##
## LEF for PtnCells ;
## created by Innovus v15.23-s045_1 on Sat Mar  7 15:14:19 2026
##

VERSION 5.8 ;

BUSBITCHARS "[]" ;
DIVIDERCHAR "/" ;

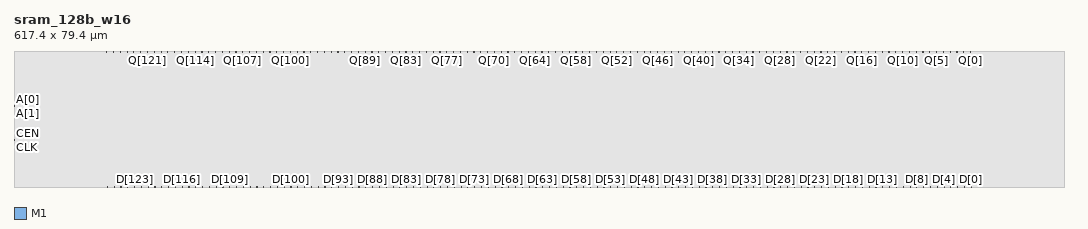
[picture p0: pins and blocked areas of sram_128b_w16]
MACRO sram_128b_w16
  CLASS BLOCK ;
  SIZE 617.4000 BY 79.4000 ;
  FOREIGN sram_128b_w16 0.0000 0.0000 ;
  ORIGIN 0 0 ;
  SYMMETRY X Y R90 ;
  PIN CLK
    DIRECTION INPUT ;
    USE SIGNAL ;
    PORT
      LAYER M1 ;
        RECT 0.0000 27.5550 0.4700 27.6450 ;
    END
  END CLK
  PIN D[127]
    DIRECTION INPUT ;
    USE SIGNAL ;
    PORT
      LAYER M1 ;
        RECT 54.8550 0.0000 54.9450 0.4700 ;
    END
  END D[127]
  PIN D[126]
    DIRECTION INPUT ;
    USE SIGNAL ;
    PORT
      LAYER M1 ;
        RECT 58.8550 0.0000 58.9450 0.4700 ;
    END
  END D[126]
  PIN D[125]
    DIRECTION INPUT ;
    USE SIGNAL ;
    PORT
      LAYER M1 ;
        RECT 62.8550 0.0000 62.9450 0.4700 ;
    END
  END D[125]
  PIN D[124]
    DIRECTION INPUT ;
    USE SIGNAL ;
    PORT
      LAYER M1 ;
        RECT 66.8550 0.0000 66.9450 0.4700 ;
    END
  END D[124]
  PIN D[123]
    DIRECTION INPUT ;
    USE SIGNAL ;
    PORT
      LAYER M1 ;
        RECT 70.8550 0.0000 70.9450 0.4700 ;
    END
  END D[123]
  PIN D[122]
    DIRECTION INPUT ;
    USE SIGNAL ;
    PORT
      LAYER M1 ;
        RECT 74.8550 0.0000 74.9450 0.4700 ;
    END
  END D[122]
  PIN D[121]
    DIRECTION INPUT ;
    USE SIGNAL ;
    PORT
      LAYER M1 ;
        RECT 78.8550 0.0000 78.9450 0.4700 ;
    END
  END D[121]
  PIN D[120]
    DIRECTION INPUT ;
    USE SIGNAL ;
    PORT
      LAYER M1 ;
        RECT 82.8550 0.0000 82.9450 0.4700 ;
    END
  END D[120]
  PIN D[119]
    DIRECTION INPUT ;
    USE SIGNAL ;
    PORT
      LAYER M1 ;
        RECT 86.8550 0.0000 86.9450 0.4700 ;
    END
  END D[119]
  PIN D[118]
    DIRECTION INPUT ;
    USE SIGNAL ;
    PORT
      LAYER M1 ;
        RECT 90.8550 0.0000 90.9450 0.4700 ;
    END
  END D[118]
  PIN D[117]
    DIRECTION INPUT ;
    USE SIGNAL ;
    PORT
      LAYER M1 ;
        RECT 94.8550 0.0000 94.9450 0.4700 ;
    END
  END D[117]
  PIN D[116]
    DIRECTION INPUT ;
    USE SIGNAL ;
    PORT
      LAYER M1 ;
        RECT 98.8550 0.0000 98.9450 0.4700 ;
    END
  END D[116]
  PIN D[115]
    DIRECTION INPUT ;
    USE SIGNAL ;
    PORT
      LAYER M1 ;
        RECT 102.8550 0.0000 102.9450 0.4700 ;
    END
  END D[115]
  PIN D[114]
    DIRECTION INPUT ;
    USE SIGNAL ;
    PORT
      LAYER M1 ;
        RECT 106.8550 0.0000 106.9450 0.4700 ;
    END
  END D[114]
  PIN D[113]
    DIRECTION INPUT ;
    USE SIGNAL ;
    PORT
      LAYER M1 ;
        RECT 110.8550 0.0000 110.9450 0.4700 ;
    END
  END D[113]
  PIN D[112]
    DIRECTION INPUT ;
    USE SIGNAL ;
    PORT
      LAYER M1 ;
        RECT 114.8550 0.0000 114.9450 0.4700 ;
    END
  END D[112]
  PIN D[111]
    DIRECTION INPUT ;
    USE SIGNAL ;
    PORT
      LAYER M1 ;
        RECT 118.8550 0.0000 118.9450 0.4700 ;
    END
  END D[111]
  PIN D[110]
    DIRECTION INPUT ;
    USE SIGNAL ;
    PORT
      LAYER M1 ;
        RECT 122.8550 0.0000 122.9450 0.4700 ;
    END
  END D[110]
  PIN D[109]
    DIRECTION INPUT ;
    USE SIGNAL ;
    PORT
      LAYER M1 ;
        RECT 126.8550 0.0000 126.9450 0.4700 ;
    END
  END D[109]
  PIN D[108]
    DIRECTION INPUT ;
    USE SIGNAL ;
    PORT
      LAYER M1 ;
        RECT 130.8550 0.0000 130.9450 0.4700 ;
    END
  END D[108]
  PIN D[107]
    DIRECTION INPUT ;
    USE SIGNAL ;
    PORT
      LAYER M1 ;
        RECT 134.8550 0.0000 134.9450 0.4700 ;
    END
  END D[107]
  PIN D[106]
    DIRECTION INPUT ;
    USE SIGNAL ;
    PORT
      LAYER M1 ;
        RECT 138.8550 0.0000 138.9450 0.4700 ;
    END
  END D[106]
  PIN D[105]
    DIRECTION INPUT ;
    USE SIGNAL ;
    PORT
      LAYER M1 ;
        RECT 142.8550 0.0000 142.9450 0.4700 ;
    END
  END D[105]
  PIN D[104]
    DIRECTION INPUT ;
    USE SIGNAL ;
    PORT
      LAYER M1 ;
        RECT 146.8550 0.0000 146.9450 0.4700 ;
    END
  END D[104]
  PIN D[103]
    DIRECTION INPUT ;
    USE SIGNAL ;
    PORT
      LAYER M1 ;
        RECT 150.8550 0.0000 150.9450 0.4700 ;
    END
  END D[103]
  PIN D[102]
    DIRECTION INPUT ;
    USE SIGNAL ;
    PORT
      LAYER M1 ;
        RECT 154.8550 0.0000 154.9450 0.4700 ;
    END
  END D[102]
  PIN D[101]
    DIRECTION INPUT ;
    USE SIGNAL ;
    PORT
      LAYER M1 ;
        RECT 158.8550 0.0000 158.9450 0.4700 ;
    END
  END D[101]
  PIN D[100]
    DIRECTION INPUT ;
    USE SIGNAL ;
    PORT
      LAYER M1 ;
        RECT 162.8550 0.0000 162.9450 0.4700 ;
    END
  END D[100]
  PIN D[99]
    DIRECTION INPUT ;
    USE SIGNAL ;
    PORT
      LAYER M1 ;
        RECT 166.8550 0.0000 166.9450 0.4700 ;
    END
  END D[99]
  PIN D[98]
    DIRECTION INPUT ;
    USE SIGNAL ;
    PORT
      LAYER M1 ;
        RECT 170.8550 0.0000 170.9450 0.4700 ;
    END
  END D[98]
  PIN D[97]
    DIRECTION INPUT ;
    USE SIGNAL ;
    PORT
      LAYER M1 ;
        RECT 174.8550 0.0000 174.9450 0.4700 ;
    END
  END D[97]
  PIN D[96]
    DIRECTION INPUT ;
    USE SIGNAL ;
    PORT
      LAYER M1 ;
        RECT 178.8550 0.0000 178.9450 0.4700 ;
    END
  END D[96]
  PIN D[95]
    DIRECTION INPUT ;
    USE SIGNAL ;
    PORT
      LAYER M1 ;
        RECT 182.8550 0.0000 182.9450 0.4700 ;
    END
  END D[95]
  PIN D[94]
    DIRECTION INPUT ;
    USE SIGNAL ;
    PORT
      LAYER M1 ;
        RECT 186.8550 0.0000 186.9450 0.4700 ;
    END
  END D[94]
  PIN D[93]
    DIRECTION INPUT ;
    USE SIGNAL ;
    PORT
      LAYER M1 ;
        RECT 190.8550 0.0000 190.9450 0.4700 ;
    END
  END D[93]
  PIN D[92]
    DIRECTION INPUT ;
    USE SIGNAL ;
    PORT
      LAYER M1 ;
        RECT 194.8550 0.0000 194.9450 0.4700 ;
    END
  END D[92]
  PIN D[91]
    DIRECTION INPUT ;
    USE SIGNAL ;
    PORT
      LAYER M1 ;
        RECT 198.8550 0.0000 198.9450 0.4700 ;
    END
  END D[91]
  PIN D[90]
    DIRECTION INPUT ;
    USE SIGNAL ;
    PORT
      LAYER M1 ;
        RECT 202.8550 0.0000 202.9450 0.4700 ;
    END
  END D[90]
  PIN D[89]
    DIRECTION INPUT ;
    USE SIGNAL ;
    PORT
      LAYER M1 ;
        RECT 206.8550 0.0000 206.9450 0.4700 ;
    END
  END D[89]
  PIN D[88]
    DIRECTION INPUT ;
    USE SIGNAL ;
    PORT
      LAYER M1 ;
        RECT 210.8550 0.0000 210.9450 0.4700 ;
    END
  END D[88]
  PIN D[87]
    DIRECTION INPUT ;
    USE SIGNAL ;
    PORT
      LAYER M1 ;
        RECT 214.8550 0.0000 214.9450 0.4700 ;
    END
  END D[87]
  PIN D[86]
    DIRECTION INPUT ;
    USE SIGNAL ;
    PORT
      LAYER M1 ;
        RECT 218.8550 0.0000 218.9450 0.4700 ;
    END
  END D[86]
  PIN D[85]
    DIRECTION INPUT ;
    USE SIGNAL ;
    PORT
      LAYER M1 ;
        RECT 222.8550 0.0000 222.9450 0.4700 ;
    END
  END D[85]
  PIN D[84]
    DIRECTION INPUT ;
    USE SIGNAL ;
    PORT
      LAYER M1 ;
        RECT 226.8550 0.0000 226.9450 0.4700 ;
    END
  END D[84]
  PIN D[83]
    DIRECTION INPUT ;
    USE SIGNAL ;
    PORT
      LAYER M1 ;
        RECT 230.8550 0.0000 230.9450 0.4700 ;
    END
  END D[83]
  PIN D[82]
    DIRECTION INPUT ;
    USE SIGNAL ;
    PORT
      LAYER M1 ;
        RECT 234.8550 0.0000 234.9450 0.4700 ;
    END
  END D[82]
  PIN D[81]
    DIRECTION INPUT ;
    USE SIGNAL ;
    PORT
      LAYER M1 ;
        RECT 238.8550 0.0000 238.9450 0.4700 ;
    END
  END D[81]
  PIN D[80]
    DIRECTION INPUT ;
    USE SIGNAL ;
    PORT
      LAYER M1 ;
        RECT 242.8550 0.0000 242.9450 0.4700 ;
    END
  END D[80]
  PIN D[79]
    DIRECTION INPUT ;
    USE SIGNAL ;
    PORT
      LAYER M1 ;
        RECT 246.8550 0.0000 246.9450 0.4700 ;
    END
  END D[79]
  PIN D[78]
    DIRECTION INPUT ;
    USE SIGNAL ;
    PORT
      LAYER M1 ;
        RECT 250.8550 0.0000 250.9450 0.4700 ;
    END
  END D[78]
  PIN D[77]
    DIRECTION INPUT ;
    USE SIGNAL ;
    PORT
      LAYER M1 ;
        RECT 254.8550 0.0000 254.9450 0.4700 ;
    END
  END D[77]
  PIN D[76]
    DIRECTION INPUT ;
    USE SIGNAL ;
    PORT
      LAYER M1 ;
        RECT 258.8550 0.0000 258.9450 0.4700 ;
    END
  END D[76]
  PIN D[75]
    DIRECTION INPUT ;
    USE SIGNAL ;
    PORT
      LAYER M1 ;
        RECT 262.8550 0.0000 262.9450 0.4700 ;
    END
  END D[75]
  PIN D[74]
    DIRECTION INPUT ;
    USE SIGNAL ;
    PORT
      LAYER M1 ;
        RECT 266.8550 0.0000 266.9450 0.4700 ;
    END
  END D[74]
  PIN D[73]
    DIRECTION INPUT ;
    USE SIGNAL ;
    PORT
      LAYER M1 ;
        RECT 270.8550 0.0000 270.9450 0.4700 ;
    END
  END D[73]
  PIN D[72]
    DIRECTION INPUT ;
    USE SIGNAL ;
    PORT
      LAYER M1 ;
        RECT 274.8550 0.0000 274.9450 0.4700 ;
    END
  END D[72]
  PIN D[71]
    DIRECTION INPUT ;
    USE SIGNAL ;
    PORT
      LAYER M1 ;
        RECT 278.8550 0.0000 278.9450 0.4700 ;
    END
  END D[71]
  PIN D[70]
    DIRECTION INPUT ;
    USE SIGNAL ;
    PORT
      LAYER M1 ;
        RECT 282.8550 0.0000 282.9450 0.4700 ;
    END
  END D[70]
  PIN D[69]
    DIRECTION INPUT ;
    USE SIGNAL ;
    PORT
      LAYER M1 ;
        RECT 286.8550 0.0000 286.9450 0.4700 ;
    END
  END D[69]
  PIN D[68]
    DIRECTION INPUT ;
    USE SIGNAL ;
    PORT
      LAYER M1 ;
        RECT 290.8550 0.0000 290.9450 0.4700 ;
    END
  END D[68]
  PIN D[67]
    DIRECTION INPUT ;
    USE SIGNAL ;
    PORT
      LAYER M1 ;
        RECT 294.8550 0.0000 294.9450 0.4700 ;
    END
  END D[67]
  PIN D[66]
    DIRECTION INPUT ;
    USE SIGNAL ;
    PORT
      LAYER M1 ;
        RECT 298.8550 0.0000 298.9450 0.4700 ;
    END
  END D[66]
  PIN D[65]
    DIRECTION INPUT ;
    USE SIGNAL ;
    PORT
      LAYER M1 ;
        RECT 302.8550 0.0000 302.9450 0.4700 ;
    END
  END D[65]
  PIN D[64]
    DIRECTION INPUT ;
    USE SIGNAL ;
    PORT
      LAYER M1 ;
        RECT 306.8550 0.0000 306.9450 0.4700 ;
    END
  END D[64]
  PIN D[63]
    DIRECTION INPUT ;
    USE SIGNAL ;
    PORT
      LAYER M1 ;
        RECT 310.8550 0.0000 310.9450 0.4700 ;
    END
  END D[63]
  PIN D[62]
    DIRECTION INPUT ;
    USE SIGNAL ;
    PORT
      LAYER M1 ;
        RECT 314.8550 0.0000 314.9450 0.4700 ;
    END
  END D[62]
  PIN D[61]
    DIRECTION INPUT ;
    USE SIGNAL ;
    PORT
      LAYER M1 ;
        RECT 318.8550 0.0000 318.9450 0.4700 ;
    END
  END D[61]
  PIN D[60]
    DIRECTION INPUT ;
    USE SIGNAL ;
    PORT
      LAYER M1 ;
        RECT 322.8550 0.0000 322.9450 0.4700 ;
    END
  END D[60]
  PIN D[59]
    DIRECTION INPUT ;
    USE SIGNAL ;
    PORT
      LAYER M1 ;
        RECT 326.8550 0.0000 326.9450 0.4700 ;
    END
  END D[59]
  PIN D[58]
    DIRECTION INPUT ;
    USE SIGNAL ;
    PORT
      LAYER M1 ;
        RECT 330.8550 0.0000 330.9450 0.4700 ;
    END
  END D[58]
  PIN D[57]
    DIRECTION INPUT ;
    USE SIGNAL ;
    PORT
      LAYER M1 ;
        RECT 334.8550 0.0000 334.9450 0.4700 ;
    END
  END D[57]
  PIN D[56]
    DIRECTION INPUT ;
    USE SIGNAL ;
    PORT
      LAYER M1 ;
        RECT 338.8550 0.0000 338.9450 0.4700 ;
    END
  END D[56]
  PIN D[55]
    DIRECTION INPUT ;
    USE SIGNAL ;
    PORT
      LAYER M1 ;
        RECT 342.8550 0.0000 342.9450 0.4700 ;
    END
  END D[55]
  PIN D[54]
    DIRECTION INPUT ;
    USE SIGNAL ;
    PORT
      LAYER M1 ;
        RECT 346.8550 0.0000 346.9450 0.4700 ;
    END
  END D[54]
  PIN D[53]
    DIRECTION INPUT ;
    USE SIGNAL ;
    PORT
      LAYER M1 ;
        RECT 350.8550 0.0000 350.9450 0.4700 ;
    END
  END D[53]
  PIN D[52]
    DIRECTION INPUT ;
    USE SIGNAL ;
    PORT
      LAYER M1 ;
        RECT 354.8550 0.0000 354.9450 0.4700 ;
    END
  END D[52]
  PIN D[51]
    DIRECTION INPUT ;
    USE SIGNAL ;
    PORT
      LAYER M1 ;
        RECT 358.8550 0.0000 358.9450 0.4700 ;
    END
  END D[51]
  PIN D[50]
    DIRECTION INPUT ;
    USE SIGNAL ;
    PORT
      LAYER M1 ;
        RECT 362.8550 0.0000 362.9450 0.4700 ;
    END
  END D[50]
  PIN D[49]
    DIRECTION INPUT ;
    USE SIGNAL ;
    PORT
      LAYER M1 ;
        RECT 366.8550 0.0000 366.9450 0.4700 ;
    END
  END D[49]
  PIN D[48]
    DIRECTION INPUT ;
    USE SIGNAL ;
    PORT
      LAYER M1 ;
        RECT 370.8550 0.0000 370.9450 0.4700 ;
    END
  END D[48]
  PIN D[47]
    DIRECTION INPUT ;
    USE SIGNAL ;
    PORT
      LAYER M1 ;
        RECT 374.8550 0.0000 374.9450 0.4700 ;
    END
  END D[47]
  PIN D[46]
    DIRECTION INPUT ;
    USE SIGNAL ;
    PORT
      LAYER M1 ;
        RECT 378.8550 0.0000 378.9450 0.4700 ;
    END
  END D[46]
  PIN D[45]
    DIRECTION INPUT ;
    USE SIGNAL ;
    PORT
      LAYER M1 ;
        RECT 382.8550 0.0000 382.9450 0.4700 ;
    END
  END D[45]
  PIN D[44]
    DIRECTION INPUT ;
    USE SIGNAL ;
    PORT
      LAYER M1 ;
        RECT 386.8550 0.0000 386.9450 0.4700 ;
    END
  END D[44]
  PIN D[43]
    DIRECTION INPUT ;
    USE SIGNAL ;
    PORT
      LAYER M1 ;
        RECT 390.8550 0.0000 390.9450 0.4700 ;
    END
  END D[43]
  PIN D[42]
    DIRECTION INPUT ;
    USE SIGNAL ;
    PORT
      LAYER M1 ;
        RECT 394.8550 0.0000 394.9450 0.4700 ;
    END
  END D[42]
  PIN D[41]
    DIRECTION INPUT ;
    USE SIGNAL ;
    PORT
      LAYER M1 ;
        RECT 398.8550 0.0000 398.9450 0.4700 ;
    END
  END D[41]
  PIN D[40]
    DIRECTION INPUT ;
    USE SIGNAL ;
    PORT
      LAYER M1 ;
        RECT 402.8550 0.0000 402.9450 0.4700 ;
    END
  END D[40]
  PIN D[39]
    DIRECTION INPUT ;
    USE SIGNAL ;
    PORT
      LAYER M1 ;
        RECT 406.8550 0.0000 406.9450 0.4700 ;
    END
  END D[39]
  PIN D[38]
    DIRECTION INPUT ;
    USE SIGNAL ;
    PORT
      LAYER M1 ;
        RECT 410.8550 0.0000 410.9450 0.4700 ;
    END
  END D[38]
  PIN D[37]
    DIRECTION INPUT ;
    USE SIGNAL ;
    PORT
      LAYER M1 ;
        RECT 414.8550 0.0000 414.9450 0.4700 ;
    END
  END D[37]
  PIN D[36]
    DIRECTION INPUT ;
    USE SIGNAL ;
    PORT
      LAYER M1 ;
        RECT 418.8550 0.0000 418.9450 0.4700 ;
    END
  END D[36]
  PIN D[35]
    DIRECTION INPUT ;
    USE SIGNAL ;
    PORT
      LAYER M1 ;
        RECT 422.8550 0.0000 422.9450 0.4700 ;
    END
  END D[35]
  PIN D[34]
    DIRECTION INPUT ;
    USE SIGNAL ;
    PORT
      LAYER M1 ;
        RECT 426.8550 0.0000 426.9450 0.4700 ;
    END
  END D[34]
  PIN D[33]
    DIRECTION INPUT ;
    USE SIGNAL ;
    PORT
      LAYER M1 ;
        RECT 430.8550 0.0000 430.9450 0.4700 ;
    END
  END D[33]
  PIN D[32]
    DIRECTION INPUT ;
    USE SIGNAL ;
    PORT
      LAYER M1 ;
        RECT 434.8550 0.0000 434.9450 0.4700 ;
    END
  END D[32]
  PIN D[31]
    DIRECTION INPUT ;
    USE SIGNAL ;
    PORT
      LAYER M1 ;
        RECT 438.8550 0.0000 438.9450 0.4700 ;
    END
  END D[31]
  PIN D[30]
    DIRECTION INPUT ;
    USE SIGNAL ;
    PORT
      LAYER M1 ;
        RECT 442.8550 0.0000 442.9450 0.4700 ;
    END
  END D[30]
  PIN D[29]
    DIRECTION INPUT ;
    USE SIGNAL ;
    PORT
      LAYER M1 ;
        RECT 446.8550 0.0000 446.9450 0.4700 ;
    END
  END D[29]
  PIN D[28]
    DIRECTION INPUT ;
    USE SIGNAL ;
    PORT
      LAYER M1 ;
        RECT 450.8550 0.0000 450.9450 0.4700 ;
    END
  END D[28]
  PIN D[27]
    DIRECTION INPUT ;
    USE SIGNAL ;
    PORT
      LAYER M1 ;
        RECT 454.8550 0.0000 454.9450 0.4700 ;
    END
  END D[27]
  PIN D[26]
    DIRECTION INPUT ;
    USE SIGNAL ;
    PORT
      LAYER M1 ;
        RECT 458.8550 0.0000 458.9450 0.4700 ;
    END
  END D[26]
  PIN D[25]
    DIRECTION INPUT ;
    USE SIGNAL ;
    PORT
      LAYER M1 ;
        RECT 462.8550 0.0000 462.9450 0.4700 ;
    END
  END D[25]
  PIN D[24]
    DIRECTION INPUT ;
    USE SIGNAL ;
    PORT
      LAYER M1 ;
        RECT 466.8550 0.0000 466.9450 0.4700 ;
    END
  END D[24]
  PIN D[23]
    DIRECTION INPUT ;
    USE SIGNAL ;
    PORT
      LAYER M1 ;
        RECT 470.8550 0.0000 470.9450 0.4700 ;
    END
  END D[23]
  PIN D[22]
    DIRECTION INPUT ;
    USE SIGNAL ;
    PORT
      LAYER M1 ;
        RECT 474.8550 0.0000 474.9450 0.4700 ;
    END
  END D[22]
  PIN D[21]
    DIRECTION INPUT ;
    USE SIGNAL ;
    PORT
      LAYER M1 ;
        RECT 478.8550 0.0000 478.9450 0.4700 ;
    END
  END D[21]
  PIN D[20]
    DIRECTION INPUT ;
    USE SIGNAL ;
    PORT
      LAYER M1 ;
        RECT 482.8550 0.0000 482.9450 0.4700 ;
    END
  END D[20]
  PIN D[19]
    DIRECTION INPUT ;
    USE SIGNAL ;
    PORT
      LAYER M1 ;
        RECT 486.8550 0.0000 486.9450 0.4700 ;
    END
  END D[19]
  PIN D[18]
    DIRECTION INPUT ;
    USE SIGNAL ;
    PORT
      LAYER M1 ;
        RECT 490.8550 0.0000 490.9450 0.4700 ;
    END
  END D[18]
  PIN D[17]
    DIRECTION INPUT ;
    USE SIGNAL ;
    PORT
      LAYER M1 ;
        RECT 494.8550 0.0000 494.9450 0.4700 ;
    END
  END D[17]
  PIN D[16]
    DIRECTION INPUT ;
    USE SIGNAL ;
    PORT
      LAYER M1 ;
        RECT 498.8550 0.0000 498.9450 0.4700 ;
    END
  END D[16]
  PIN D[15]
    DIRECTION INPUT ;
    USE SIGNAL ;
    PORT
      LAYER M1 ;
        RECT 502.8550 0.0000 502.9450 0.4700 ;
    END
  END D[15]
  PIN D[14]
    DIRECTION INPUT ;
    USE SIGNAL ;
    PORT
      LAYER M1 ;
        RECT 506.8550 0.0000 506.9450 0.4700 ;
    END
  END D[14]
  PIN D[13]
    DIRECTION INPUT ;
    USE SIGNAL ;
    PORT
      LAYER M1 ;
        RECT 510.8550 0.0000 510.9450 0.4700 ;
    END
  END D[13]
  PIN D[12]
    DIRECTION INPUT ;
    USE SIGNAL ;
    PORT
      LAYER M1 ;
        RECT 514.8550 0.0000 514.9450 0.4700 ;
    END
  END D[12]
  PIN D[11]
    DIRECTION INPUT ;
    USE SIGNAL ;
    PORT
      LAYER M1 ;
        RECT 518.8550 0.0000 518.9450 0.4700 ;
    END
  END D[11]
  PIN D[10]
    DIRECTION INPUT ;
    USE SIGNAL ;
    PORT
      LAYER M1 ;
        RECT 522.8550 0.0000 522.9450 0.4700 ;
    END
  END D[10]
  PIN D[9]
    DIRECTION INPUT ;
    USE SIGNAL ;
    PORT
      LAYER M1 ;
        RECT 526.8550 0.0000 526.9450 0.4700 ;
    END
  END D[9]
  PIN D[8]
    DIRECTION INPUT ;
    USE SIGNAL ;
    PORT
      LAYER M1 ;
        RECT 530.8550 0.0000 530.9450 0.4700 ;
    END
  END D[8]
  PIN D[7]
    DIRECTION INPUT ;
    USE SIGNAL ;
    PORT
      LAYER M1 ;
        RECT 534.8550 0.0000 534.9450 0.4700 ;
    END
  END D[7]
  PIN D[6]
    DIRECTION INPUT ;
    USE SIGNAL ;
    PORT
      LAYER M1 ;
        RECT 538.8550 0.0000 538.9450 0.4700 ;
    END
  END D[6]
  PIN D[5]
    DIRECTION INPUT ;
    USE SIGNAL ;
    PORT
      LAYER M1 ;
        RECT 542.8550 0.0000 542.9450 0.4700 ;
    END
  END D[5]
  PIN D[4]
    DIRECTION INPUT ;
    USE SIGNAL ;
    PORT
      LAYER M1 ;
        RECT 546.8550 0.0000 546.9450 0.4700 ;
    END
  END D[4]
  PIN D[3]
    DIRECTION INPUT ;
    USE SIGNAL ;
    PORT
      LAYER M1 ;
        RECT 550.8550 0.0000 550.9450 0.4700 ;
    END
  END D[3]
  PIN D[2]
    DIRECTION INPUT ;
    USE SIGNAL ;
    PORT
      LAYER M1 ;
        RECT 554.8550 0.0000 554.9450 0.4700 ;
    END
  END D[2]
  PIN D[1]
    DIRECTION INPUT ;
    USE SIGNAL ;
    PORT
      LAYER M1 ;
        RECT 558.8550 0.0000 558.9450 0.4700 ;
    END
  END D[1]
  PIN D[0]
    DIRECTION INPUT ;
    USE SIGNAL ;
    PORT
      LAYER M1 ;
        RECT 562.8550 0.0000 562.9450 0.4700 ;
    END
  END D[0]
  PIN Q[127]
    DIRECTION OUTPUT ;
    USE SIGNAL ;
    PORT
      LAYER M1 ;
        RECT 54.4550 78.9300 54.5450 79.4000 ;
    END
  END Q[127]
  PIN Q[126]
    DIRECTION OUTPUT ;
    USE SIGNAL ;
    PORT
      LAYER M1 ;
        RECT 58.4550 78.9300 58.5450 79.4000 ;
    END
  END Q[126]
  PIN Q[125]
    DIRECTION OUTPUT ;
    USE SIGNAL ;
    PORT
      LAYER M1 ;
        RECT 62.4550 78.9300 62.5450 79.4000 ;
    END
  END Q[125]
  PIN Q[124]
    DIRECTION OUTPUT ;
    USE SIGNAL ;
    PORT
      LAYER M1 ;
        RECT 66.4550 78.9300 66.5450 79.4000 ;
    END
  END Q[124]
  PIN Q[123]
    DIRECTION OUTPUT ;
    USE SIGNAL ;
    PORT
      LAYER M1 ;
        RECT 70.4550 78.9300 70.5450 79.4000 ;
    END
  END Q[123]
  PIN Q[122]
    DIRECTION OUTPUT ;
    USE SIGNAL ;
    PORT
      LAYER M1 ;
        RECT 74.4550 78.9300 74.5450 79.4000 ;
    END
  END Q[122]
  PIN Q[121]
    DIRECTION OUTPUT ;
    USE SIGNAL ;
    PORT
      LAYER M1 ;
        RECT 78.4550 78.9300 78.5450 79.4000 ;
    END
  END Q[121]
  PIN Q[120]
    DIRECTION OUTPUT ;
    USE SIGNAL ;
    PORT
      LAYER M1 ;
        RECT 82.4550 78.9300 82.5450 79.4000 ;
    END
  END Q[120]
  PIN Q[119]
    DIRECTION OUTPUT ;
    USE SIGNAL ;
    PORT
      LAYER M1 ;
        RECT 86.4550 78.9300 86.5450 79.4000 ;
    END
  END Q[119]
  PIN Q[118]
    DIRECTION OUTPUT ;
    USE SIGNAL ;
    PORT
      LAYER M1 ;
        RECT 90.4550 78.9300 90.5450 79.4000 ;
    END
  END Q[118]
  PIN Q[117]
    DIRECTION OUTPUT ;
    USE SIGNAL ;
    PORT
      LAYER M1 ;
        RECT 94.4550 78.9300 94.5450 79.4000 ;
    END
  END Q[117]
  PIN Q[116]
    DIRECTION OUTPUT ;
    USE SIGNAL ;
    PORT
      LAYER M1 ;
        RECT 98.4550 78.9300 98.5450 79.4000 ;
    END
  END Q[116]
  PIN Q[115]
    DIRECTION OUTPUT ;
    USE SIGNAL ;
    PORT
      LAYER M1 ;
        RECT 102.4550 78.9300 102.5450 79.4000 ;
    END
  END Q[115]
  PIN Q[114]
    DIRECTION OUTPUT ;
    USE SIGNAL ;
    PORT
      LAYER M1 ;
        RECT 106.4550 78.9300 106.5450 79.4000 ;
    END
  END Q[114]
  PIN Q[113]
    DIRECTION OUTPUT ;
    USE SIGNAL ;
    PORT
      LAYER M1 ;
        RECT 110.4550 78.9300 110.5450 79.4000 ;
    END
  END Q[113]
  PIN Q[112]
    DIRECTION OUTPUT ;
    USE SIGNAL ;
    PORT
      LAYER M1 ;
        RECT 114.4550 78.9300 114.5450 79.4000 ;
    END
  END Q[112]
  PIN Q[111]
    DIRECTION OUTPUT ;
    USE SIGNAL ;
    PORT
      LAYER M1 ;
        RECT 118.4550 78.9300 118.5450 79.4000 ;
    END
  END Q[111]
  PIN Q[110]
    DIRECTION OUTPUT ;
    USE SIGNAL ;
    PORT
      LAYER M1 ;
        RECT 122.4550 78.9300 122.5450 79.4000 ;
    END
  END Q[110]
  PIN Q[109]
    DIRECTION OUTPUT ;
    USE SIGNAL ;
    PORT
      LAYER M1 ;
        RECT 126.4550 78.9300 126.5450 79.4000 ;
    END
  END Q[109]
  PIN Q[108]
    DIRECTION OUTPUT ;
    USE SIGNAL ;
    PORT
      LAYER M1 ;
        RECT 130.4550 78.9300 130.5450 79.4000 ;
    END
  END Q[108]
  PIN Q[107]
    DIRECTION OUTPUT ;
    USE SIGNAL ;
    PORT
      LAYER M1 ;
        RECT 134.4550 78.9300 134.5450 79.4000 ;
    END
  END Q[107]
  PIN Q[106]
    DIRECTION OUTPUT ;
    USE SIGNAL ;
    PORT
      LAYER M1 ;
        RECT 138.4550 78.9300 138.5450 79.4000 ;
    END
  END Q[106]
  PIN Q[105]
    DIRECTION OUTPUT ;
    USE SIGNAL ;
    PORT
      LAYER M1 ;
        RECT 142.4550 78.9300 142.5450 79.4000 ;
    END
  END Q[105]
  PIN Q[104]
    DIRECTION OUTPUT ;
    USE SIGNAL ;
    PORT
      LAYER M1 ;
        RECT 146.4550 78.9300 146.5450 79.4000 ;
    END
  END Q[104]
  PIN Q[103]
    DIRECTION OUTPUT ;
    USE SIGNAL ;
    PORT
      LAYER M1 ;
        RECT 150.4550 78.9300 150.5450 79.4000 ;
    END
  END Q[103]
  PIN Q[102]
    DIRECTION OUTPUT ;
    USE SIGNAL ;
    PORT
      LAYER M1 ;
        RECT 154.4550 78.9300 154.5450 79.4000 ;
    END
  END Q[102]
  PIN Q[101]
    DIRECTION OUTPUT ;
    USE SIGNAL ;
    PORT
      LAYER M1 ;
        RECT 158.4550 78.9300 158.5450 79.4000 ;
    END
  END Q[101]
  PIN Q[100]
    DIRECTION OUTPUT ;
    USE SIGNAL ;
    PORT
      LAYER M1 ;
        RECT 162.4550 78.9300 162.5450 79.4000 ;
    END
  END Q[100]
  PIN Q[99]
    DIRECTION OUTPUT ;
    USE SIGNAL ;
    PORT
      LAYER M1 ;
        RECT 166.4550 78.9300 166.5450 79.4000 ;
    END
  END Q[99]
  PIN Q[98]
    DIRECTION OUTPUT ;
    USE SIGNAL ;
    PORT
      LAYER M1 ;
        RECT 170.4550 78.9300 170.5450 79.4000 ;
    END
  END Q[98]
  PIN Q[97]
    DIRECTION OUTPUT ;
    USE SIGNAL ;
    PORT
      LAYER M1 ;
        RECT 174.4550 78.9300 174.5450 79.4000 ;
    END
  END Q[97]
  PIN Q[96]
    DIRECTION OUTPUT ;
    USE SIGNAL ;
    PORT
      LAYER M1 ;
        RECT 178.4550 78.9300 178.5450 79.4000 ;
    END
  END Q[96]
  PIN Q[95]
    DIRECTION OUTPUT ;
    USE SIGNAL ;
    PORT
      LAYER M1 ;
        RECT 182.4550 78.9300 182.5450 79.4000 ;
    END
  END Q[95]
  PIN Q[94]
    DIRECTION OUTPUT ;
    USE SIGNAL ;
    PORT
      LAYER M1 ;
        RECT 186.4550 78.9300 186.5450 79.4000 ;
    END
  END Q[94]
  PIN Q[93]
    DIRECTION OUTPUT ;
    USE SIGNAL ;
    PORT
      LAYER M1 ;
        RECT 190.4550 78.9300 190.5450 79.4000 ;
    END
  END Q[93]
  PIN Q[92]
    DIRECTION OUTPUT ;
    USE SIGNAL ;
    PORT
      LAYER M1 ;
        RECT 194.4550 78.9300 194.5450 79.4000 ;
    END
  END Q[92]
  PIN Q[91]
    DIRECTION OUTPUT ;
    USE SIGNAL ;
    PORT
      LAYER M1 ;
        RECT 198.4550 78.9300 198.5450 79.4000 ;
    END
  END Q[91]
  PIN Q[90]
    DIRECTION OUTPUT ;
    USE SIGNAL ;
    PORT
      LAYER M1 ;
        RECT 202.4550 78.9300 202.5450 79.4000 ;
    END
  END Q[90]
  PIN Q[89]
    DIRECTION OUTPUT ;
    USE SIGNAL ;
    PORT
      LAYER M1 ;
        RECT 206.4550 78.9300 206.5450 79.4000 ;
    END
  END Q[89]
  PIN Q[88]
    DIRECTION OUTPUT ;
    USE SIGNAL ;
    PORT
      LAYER M1 ;
        RECT 210.4550 78.9300 210.5450 79.4000 ;
    END
  END Q[88]
  PIN Q[87]
    DIRECTION OUTPUT ;
    USE SIGNAL ;
    PORT
      LAYER M1 ;
        RECT 214.4550 78.9300 214.5450 79.4000 ;
    END
  END Q[87]
  PIN Q[86]
    DIRECTION OUTPUT ;
    USE SIGNAL ;
    PORT
      LAYER M1 ;
        RECT 218.4550 78.9300 218.5450 79.4000 ;
    END
  END Q[86]
  PIN Q[85]
    DIRECTION OUTPUT ;
    USE SIGNAL ;
    PORT
      LAYER M1 ;
        RECT 222.4550 78.9300 222.5450 79.4000 ;
    END
  END Q[85]
  PIN Q[84]
    DIRECTION OUTPUT ;
    USE SIGNAL ;
    PORT
      LAYER M1 ;
        RECT 226.4550 78.9300 226.5450 79.4000 ;
    END
  END Q[84]
  PIN Q[83]
    DIRECTION OUTPUT ;
    USE SIGNAL ;
    PORT
      LAYER M1 ;
        RECT 230.4550 78.9300 230.5450 79.4000 ;
    END
  END Q[83]
  PIN Q[82]
    DIRECTION OUTPUT ;
    USE SIGNAL ;
    PORT
      LAYER M1 ;
        RECT 234.4550 78.9300 234.5450 79.4000 ;
    END
  END Q[82]
  PIN Q[81]
    DIRECTION OUTPUT ;
    USE SIGNAL ;
    PORT
      LAYER M1 ;
        RECT 238.4550 78.9300 238.5450 79.4000 ;
    END
  END Q[81]
  PIN Q[80]
    DIRECTION OUTPUT ;
    USE SIGNAL ;
    PORT
      LAYER M1 ;
        RECT 242.4550 78.9300 242.5450 79.4000 ;
    END
  END Q[80]
  PIN Q[79]
    DIRECTION OUTPUT ;
    USE SIGNAL ;
    PORT
      LAYER M1 ;
        RECT 246.4550 78.9300 246.5450 79.4000 ;
    END
  END Q[79]
  PIN Q[78]
    DIRECTION OUTPUT ;
    USE SIGNAL ;
    PORT
      LAYER M1 ;
        RECT 250.4550 78.9300 250.5450 79.4000 ;
    END
  END Q[78]
  PIN Q[77]
    DIRECTION OUTPUT ;
    USE SIGNAL ;
    PORT
      LAYER M1 ;
        RECT 254.4550 78.9300 254.5450 79.4000 ;
    END
  END Q[77]
  PIN Q[76]
    DIRECTION OUTPUT ;
    USE SIGNAL ;
    PORT
      LAYER M1 ;
        RECT 258.4550 78.9300 258.5450 79.4000 ;
    END
  END Q[76]
  PIN Q[75]
    DIRECTION OUTPUT ;
    USE SIGNAL ;
    PORT
      LAYER M1 ;
        RECT 262.4550 78.9300 262.5450 79.4000 ;
    END
  END Q[75]
  PIN Q[74]
    DIRECTION OUTPUT ;
    USE SIGNAL ;
    PORT
      LAYER M1 ;
        RECT 266.4550 78.9300 266.5450 79.4000 ;
    END
  END Q[74]
  PIN Q[73]
    DIRECTION OUTPUT ;
    USE SIGNAL ;
    PORT
      LAYER M1 ;
        RECT 270.4550 78.9300 270.5450 79.4000 ;
    END
  END Q[73]
  PIN Q[72]
    DIRECTION OUTPUT ;
    USE SIGNAL ;
    PORT
      LAYER M1 ;
        RECT 274.4550 78.9300 274.5450 79.4000 ;
    END
  END Q[72]
  PIN Q[71]
    DIRECTION OUTPUT ;
    USE SIGNAL ;
    PORT
      LAYER M1 ;
        RECT 278.4550 78.9300 278.5450 79.4000 ;
    END
  END Q[71]
  PIN Q[70]
    DIRECTION OUTPUT ;
    USE SIGNAL ;
    PORT
      LAYER M1 ;
        RECT 282.4550 78.9300 282.5450 79.4000 ;
    END
  END Q[70]
  PIN Q[69]
    DIRECTION OUTPUT ;
    USE SIGNAL ;
    PORT
      LAYER M1 ;
        RECT 286.4550 78.9300 286.5450 79.4000 ;
    END
  END Q[69]
  PIN Q[68]
    DIRECTION OUTPUT ;
    USE SIGNAL ;
    PORT
      LAYER M1 ;
        RECT 290.4550 78.9300 290.5450 79.4000 ;
    END
  END Q[68]
  PIN Q[67]
    DIRECTION OUTPUT ;
    USE SIGNAL ;
    PORT
      LAYER M1 ;
        RECT 294.4550 78.9300 294.5450 79.4000 ;
    END
  END Q[67]
  PIN Q[66]
    DIRECTION OUTPUT ;
    USE SIGNAL ;
    PORT
      LAYER M1 ;
        RECT 298.4550 78.9300 298.5450 79.4000 ;
    END
  END Q[66]
  PIN Q[65]
    DIRECTION OUTPUT ;
    USE SIGNAL ;
    PORT
      LAYER M1 ;
        RECT 302.4550 78.9300 302.5450 79.4000 ;
    END
  END Q[65]
  PIN Q[64]
    DIRECTION OUTPUT ;
    USE SIGNAL ;
    PORT
      LAYER M1 ;
        RECT 306.4550 78.9300 306.5450 79.4000 ;
    END
  END Q[64]
  PIN Q[63]
    DIRECTION OUTPUT ;
    USE SIGNAL ;
    PORT
      LAYER M1 ;
        RECT 310.4550 78.9300 310.5450 79.4000 ;
    END
  END Q[63]
  PIN Q[62]
    DIRECTION OUTPUT ;
    USE SIGNAL ;
    PORT
      LAYER M1 ;
        RECT 314.4550 78.9300 314.5450 79.4000 ;
    END
  END Q[62]
  PIN Q[61]
    DIRECTION OUTPUT ;
    USE SIGNAL ;
    PORT
      LAYER M1 ;
        RECT 318.4550 78.9300 318.5450 79.4000 ;
    END
  END Q[61]
  PIN Q[60]
    DIRECTION OUTPUT ;
    USE SIGNAL ;
    PORT
      LAYER M1 ;
        RECT 322.4550 78.9300 322.5450 79.4000 ;
    END
  END Q[60]
  PIN Q[59]
    DIRECTION OUTPUT ;
    USE SIGNAL ;
    PORT
      LAYER M1 ;
        RECT 326.4550 78.9300 326.5450 79.4000 ;
    END
  END Q[59]
  PIN Q[58]
    DIRECTION OUTPUT ;
    USE SIGNAL ;
    PORT
      LAYER M1 ;
        RECT 330.4550 78.9300 330.5450 79.4000 ;
    END
  END Q[58]
  PIN Q[57]
    DIRECTION OUTPUT ;
    USE SIGNAL ;
    PORT
      LAYER M1 ;
        RECT 334.4550 78.9300 334.5450 79.4000 ;
    END
  END Q[57]
  PIN Q[56]
    DIRECTION OUTPUT ;
    USE SIGNAL ;
    PORT
      LAYER M1 ;
        RECT 338.4550 78.9300 338.5450 79.4000 ;
    END
  END Q[56]
  PIN Q[55]
    DIRECTION OUTPUT ;
    USE SIGNAL ;
    PORT
      LAYER M1 ;
        RECT 342.4550 78.9300 342.5450 79.4000 ;
    END
  END Q[55]
  PIN Q[54]
    DIRECTION OUTPUT ;
    USE SIGNAL ;
    PORT
      LAYER M1 ;
        RECT 346.4550 78.9300 346.5450 79.4000 ;
    END
  END Q[54]
  PIN Q[53]
    DIRECTION OUTPUT ;
    USE SIGNAL ;
    PORT
      LAYER M1 ;
        RECT 350.4550 78.9300 350.5450 79.4000 ;
    END
  END Q[53]
  PIN Q[52]
    DIRECTION OUTPUT ;
    USE SIGNAL ;
    PORT
      LAYER M1 ;
        RECT 354.4550 78.9300 354.5450 79.4000 ;
    END
  END Q[52]
  PIN Q[51]
    DIRECTION OUTPUT ;
    USE SIGNAL ;
    PORT
      LAYER M1 ;
        RECT 358.4550 78.9300 358.5450 79.4000 ;
    END
  END Q[51]
  PIN Q[50]
    DIRECTION OUTPUT ;
    USE SIGNAL ;
    PORT
      LAYER M1 ;
        RECT 362.4550 78.9300 362.5450 79.4000 ;
    END
  END Q[50]
  PIN Q[49]
    DIRECTION OUTPUT ;
    USE SIGNAL ;
    PORT
      LAYER M1 ;
        RECT 366.4550 78.9300 366.5450 79.4000 ;
    END
  END Q[49]
  PIN Q[48]
    DIRECTION OUTPUT ;
    USE SIGNAL ;
    PORT
      LAYER M1 ;
        RECT 370.4550 78.9300 370.5450 79.4000 ;
    END
  END Q[48]
  PIN Q[47]
    DIRECTION OUTPUT ;
    USE SIGNAL ;
    PORT
      LAYER M1 ;
        RECT 374.4550 78.9300 374.5450 79.4000 ;
    END
  END Q[47]
  PIN Q[46]
    DIRECTION OUTPUT ;
    USE SIGNAL ;
    PORT
      LAYER M1 ;
        RECT 378.4550 78.9300 378.5450 79.4000 ;
    END
  END Q[46]
  PIN Q[45]
    DIRECTION OUTPUT ;
    USE SIGNAL ;
    PORT
      LAYER M1 ;
        RECT 382.4550 78.9300 382.5450 79.4000 ;
    END
  END Q[45]
  PIN Q[44]
    DIRECTION OUTPUT ;
    USE SIGNAL ;
    PORT
      LAYER M1 ;
        RECT 386.4550 78.9300 386.5450 79.4000 ;
    END
  END Q[44]
  PIN Q[43]
    DIRECTION OUTPUT ;
    USE SIGNAL ;
    PORT
      LAYER M1 ;
        RECT 390.4550 78.9300 390.5450 79.4000 ;
    END
  END Q[43]
  PIN Q[42]
    DIRECTION OUTPUT ;
    USE SIGNAL ;
    PORT
      LAYER M1 ;
        RECT 394.4550 78.9300 394.5450 79.4000 ;
    END
  END Q[42]
  PIN Q[41]
    DIRECTION OUTPUT ;
    USE SIGNAL ;
    PORT
      LAYER M1 ;
        RECT 398.4550 78.9300 398.5450 79.4000 ;
    END
  END Q[41]
  PIN Q[40]
    DIRECTION OUTPUT ;
    USE SIGNAL ;
    PORT
      LAYER M1 ;
        RECT 402.4550 78.9300 402.5450 79.4000 ;
    END
  END Q[40]
  PIN Q[39]
    DIRECTION OUTPUT ;
    USE SIGNAL ;
    PORT
      LAYER M1 ;
        RECT 406.4550 78.9300 406.5450 79.4000 ;
    END
  END Q[39]
  PIN Q[38]
    DIRECTION OUTPUT ;
    USE SIGNAL ;
    PORT
      LAYER M1 ;
        RECT 410.4550 78.9300 410.5450 79.4000 ;
    END
  END Q[38]
  PIN Q[37]
    DIRECTION OUTPUT ;
    USE SIGNAL ;
    PORT
      LAYER M1 ;
        RECT 414.4550 78.9300 414.5450 79.4000 ;
    END
  END Q[37]
  PIN Q[36]
    DIRECTION OUTPUT ;
    USE SIGNAL ;
    PORT
      LAYER M1 ;
        RECT 418.4550 78.9300 418.5450 79.4000 ;
    END
  END Q[36]
  PIN Q[35]
    DIRECTION OUTPUT ;
    USE SIGNAL ;
    PORT
      LAYER M1 ;
        RECT 422.4550 78.9300 422.5450 79.4000 ;
    END
  END Q[35]
  PIN Q[34]
    DIRECTION OUTPUT ;
    USE SIGNAL ;
    PORT
      LAYER M1 ;
        RECT 426.4550 78.9300 426.5450 79.4000 ;
    END
  END Q[34]
  PIN Q[33]
    DIRECTION OUTPUT ;
    USE SIGNAL ;
    PORT
      LAYER M1 ;
        RECT 430.4550 78.9300 430.5450 79.4000 ;
    END
  END Q[33]
  PIN Q[32]
    DIRECTION OUTPUT ;
    USE SIGNAL ;
    PORT
      LAYER M1 ;
        RECT 434.4550 78.9300 434.5450 79.4000 ;
    END
  END Q[32]
  PIN Q[31]
    DIRECTION OUTPUT ;
    USE SIGNAL ;
    PORT
      LAYER M1 ;
        RECT 438.4550 78.9300 438.5450 79.4000 ;
    END
  END Q[31]
  PIN Q[30]
    DIRECTION OUTPUT ;
    USE SIGNAL ;
    PORT
      LAYER M1 ;
        RECT 442.4550 78.9300 442.5450 79.4000 ;
    END
  END Q[30]
  PIN Q[29]
    DIRECTION OUTPUT ;
    USE SIGNAL ;
    PORT
      LAYER M1 ;
        RECT 446.4550 78.9300 446.5450 79.4000 ;
    END
  END Q[29]
  PIN Q[28]
    DIRECTION OUTPUT ;
    USE SIGNAL ;
    PORT
      LAYER M1 ;
        RECT 450.4550 78.9300 450.5450 79.4000 ;
    END
  END Q[28]
  PIN Q[27]
    DIRECTION OUTPUT ;
    USE SIGNAL ;
    PORT
      LAYER M1 ;
        RECT 454.4550 78.9300 454.5450 79.4000 ;
    END
  END Q[27]
  PIN Q[26]
    DIRECTION OUTPUT ;
    USE SIGNAL ;
    PORT
      LAYER M1 ;
        RECT 458.4550 78.9300 458.5450 79.4000 ;
    END
  END Q[26]
  PIN Q[25]
    DIRECTION OUTPUT ;
    USE SIGNAL ;
    PORT
      LAYER M1 ;
        RECT 462.4550 78.9300 462.5450 79.4000 ;
    END
  END Q[25]
  PIN Q[24]
    DIRECTION OUTPUT ;
    USE SIGNAL ;
    PORT
      LAYER M1 ;
        RECT 466.4550 78.9300 466.5450 79.4000 ;
    END
  END Q[24]
  PIN Q[23]
    DIRECTION OUTPUT ;
    USE SIGNAL ;
    PORT
      LAYER M1 ;
        RECT 470.4550 78.9300 470.5450 79.4000 ;
    END
  END Q[23]
  PIN Q[22]
    DIRECTION OUTPUT ;
    USE SIGNAL ;
    PORT
      LAYER M1 ;
        RECT 474.4550 78.9300 474.5450 79.4000 ;
    END
  END Q[22]
  PIN Q[21]
    DIRECTION OUTPUT ;
    USE SIGNAL ;
    PORT
      LAYER M1 ;
        RECT 478.4550 78.9300 478.5450 79.4000 ;
    END
  END Q[21]
  PIN Q[20]
    DIRECTION OUTPUT ;
    USE SIGNAL ;
    PORT
      LAYER M1 ;
        RECT 482.4550 78.9300 482.5450 79.4000 ;
    END
  END Q[20]
  PIN Q[19]
    DIRECTION OUTPUT ;
    USE SIGNAL ;
    PORT
      LAYER M1 ;
        RECT 486.4550 78.9300 486.5450 79.4000 ;
    END
  END Q[19]
  PIN Q[18]
    DIRECTION OUTPUT ;
    USE SIGNAL ;
    PORT
      LAYER M1 ;
        RECT 490.4550 78.9300 490.5450 79.4000 ;
    END
  END Q[18]
  PIN Q[17]
    DIRECTION OUTPUT ;
    USE SIGNAL ;
    PORT
      LAYER M1 ;
        RECT 494.4550 78.9300 494.5450 79.4000 ;
    END
  END Q[17]
  PIN Q[16]
    DIRECTION OUTPUT ;
    USE SIGNAL ;
    PORT
      LAYER M1 ;
        RECT 498.4550 78.9300 498.5450 79.4000 ;
    END
  END Q[16]
  PIN Q[15]
    DIRECTION OUTPUT ;
    USE SIGNAL ;
    PORT
      LAYER M1 ;
        RECT 502.4550 78.9300 502.5450 79.4000 ;
    END
  END Q[15]
  PIN Q[14]
    DIRECTION OUTPUT ;
    USE SIGNAL ;
    PORT
      LAYER M1 ;
        RECT 506.4550 78.9300 506.5450 79.4000 ;
    END
  END Q[14]
  PIN Q[13]
    DIRECTION OUTPUT ;
    USE SIGNAL ;
    PORT
      LAYER M1 ;
        RECT 510.4550 78.9300 510.5450 79.4000 ;
    END
  END Q[13]
  PIN Q[12]
    DIRECTION OUTPUT ;
    USE SIGNAL ;
    PORT
      LAYER M1 ;
        RECT 514.4550 78.9300 514.5450 79.4000 ;
    END
  END Q[12]
  PIN Q[11]
    DIRECTION OUTPUT ;
    USE SIGNAL ;
    PORT
      LAYER M1 ;
        RECT 518.4550 78.9300 518.5450 79.4000 ;
    END
  END Q[11]
  PIN Q[10]
    DIRECTION OUTPUT ;
    USE SIGNAL ;
    PORT
      LAYER M1 ;
        RECT 522.4550 78.9300 522.5450 79.4000 ;
    END
  END Q[10]
  PIN Q[9]
    DIRECTION OUTPUT ;
    USE SIGNAL ;
    PORT
      LAYER M1 ;
        RECT 526.4550 78.9300 526.5450 79.4000 ;
    END
  END Q[9]
  PIN Q[8]
    DIRECTION OUTPUT ;
    USE SIGNAL ;
    PORT
      LAYER M1 ;
        RECT 530.4550 78.9300 530.5450 79.4000 ;
    END
  END Q[8]
  PIN Q[7]
    DIRECTION OUTPUT ;
    USE SIGNAL ;
    PORT
      LAYER M1 ;
        RECT 534.4550 78.9300 534.5450 79.4000 ;
    END
  END Q[7]
  PIN Q[6]
    DIRECTION OUTPUT ;
    USE SIGNAL ;
    PORT
      LAYER M1 ;
        RECT 538.4550 78.9300 538.5450 79.4000 ;
    END
  END Q[6]
  PIN Q[5]
    DIRECTION OUTPUT ;
    USE SIGNAL ;
    PORT
      LAYER M1 ;
        RECT 542.4550 78.9300 542.5450 79.4000 ;
    END
  END Q[5]
  PIN Q[4]
    DIRECTION OUTPUT ;
    USE SIGNAL ;
    PORT
      LAYER M1 ;
        RECT 546.4550 78.9300 546.5450 79.4000 ;
    END
  END Q[4]
  PIN Q[3]
    DIRECTION OUTPUT ;
    USE SIGNAL ;
    PORT
      LAYER M1 ;
        RECT 550.4550 78.9300 550.5450 79.4000 ;
    END
  END Q[3]
  PIN Q[2]
    DIRECTION OUTPUT ;
    USE SIGNAL ;
    PORT
      LAYER M1 ;
        RECT 554.4550 78.9300 554.5450 79.4000 ;
    END
  END Q[2]
  PIN Q[1]
    DIRECTION OUTPUT ;
    USE SIGNAL ;
    PORT
      LAYER M1 ;
        RECT 558.4550 78.9300 558.5450 79.4000 ;
    END
  END Q[1]
  PIN Q[0]
    DIRECTION OUTPUT ;
    USE SIGNAL ;
    PORT
      LAYER M1 ;
        RECT 562.4550 78.9300 562.5450 79.4000 ;
    END
  END Q[0]
  PIN CEN
    DIRECTION INPUT ;
    USE SIGNAL ;
    PORT
      LAYER M1 ;
        RECT 0.0000 31.5550 0.4700 31.6450 ;
    END
  END CEN
  PIN WEN
    DIRECTION INPUT ;
    USE SIGNAL ;
    PORT
      LAYER M1 ;
        RECT 0.0000 35.5550 0.4700 35.6450 ;
    END
  END WEN
  PIN A[3]
    DIRECTION INPUT ;
    USE SIGNAL ;
    PORT
      LAYER M1 ;
        RECT 0.0000 39.5550 0.4700 39.6450 ;
    END
  END A[3]
  PIN A[2]
    DIRECTION INPUT ;
    USE SIGNAL ;
    PORT
      LAYER M1 ;
        RECT 0.0000 43.5550 0.4700 43.6450 ;
    END
  END A[2]
  PIN A[1]
    DIRECTION INPUT ;
    USE SIGNAL ;
    PORT
      LAYER M1 ;
        RECT 0.0000 47.5550 0.4700 47.6450 ;
    END
  END A[1]
  PIN A[0]
    DIRECTION INPUT ;
    USE SIGNAL ;
    PORT
      LAYER M1 ;
        RECT 0.0000 51.5550 0.4700 51.6450 ;
    END
  END A[0]
  OBS
    LAYER M1 ;
      RECT 562.7050 78.7700 617.4000 79.4000 ;
      RECT 558.7050 78.7700 562.2950 79.4000 ;
      RECT 554.7050 78.7700 558.2950 79.4000 ;
      RECT 550.7050 78.7700 554.2950 79.4000 ;
      RECT 546.7050 78.7700 550.2950 79.4000 ;
      RECT 542.7050 78.7700 546.2950 79.4000 ;
      RECT 538.7050 78.7700 542.2950 79.4000 ;
      RECT 534.7050 78.7700 538.2950 79.4000 ;
      RECT 530.7050 78.7700 534.2950 79.4000 ;
      RECT 526.7050 78.7700 530.2950 79.4000 ;
      RECT 522.7050 78.7700 526.2950 79.4000 ;
      RECT 518.7050 78.7700 522.2950 79.4000 ;
      RECT 514.7050 78.7700 518.2950 79.4000 ;
      RECT 510.7050 78.7700 514.2950 79.4000 ;
      RECT 506.7050 78.7700 510.2950 79.4000 ;
      RECT 502.7050 78.7700 506.2950 79.4000 ;
      RECT 498.7050 78.7700 502.2950 79.4000 ;
      RECT 494.7050 78.7700 498.2950 79.4000 ;
      RECT 490.7050 78.7700 494.2950 79.4000 ;
      RECT 486.7050 78.7700 490.2950 79.4000 ;
      RECT 482.7050 78.7700 486.2950 79.4000 ;
      RECT 478.7050 78.7700 482.2950 79.4000 ;
      RECT 474.7050 78.7700 478.2950 79.4000 ;
      RECT 470.7050 78.7700 474.2950 79.4000 ;
      RECT 466.7050 78.7700 470.2950 79.4000 ;
      RECT 462.7050 78.7700 466.2950 79.4000 ;
      RECT 458.7050 78.7700 462.2950 79.4000 ;
      RECT 454.7050 78.7700 458.2950 79.4000 ;
      RECT 450.7050 78.7700 454.2950 79.4000 ;
      RECT 446.7050 78.7700 450.2950 79.4000 ;
      RECT 442.7050 78.7700 446.2950 79.4000 ;
      RECT 438.7050 78.7700 442.2950 79.4000 ;
      RECT 434.7050 78.7700 438.2950 79.4000 ;
      RECT 430.7050 78.7700 434.2950 79.4000 ;
      RECT 426.7050 78.7700 430.2950 79.4000 ;
      RECT 422.7050 78.7700 426.2950 79.4000 ;
      RECT 418.7050 78.7700 422.2950 79.4000 ;
      RECT 414.7050 78.7700 418.2950 79.4000 ;
      RECT 410.7050 78.7700 414.2950 79.4000 ;
      RECT 406.7050 78.7700 410.2950 79.4000 ;
      RECT 402.7050 78.7700 406.2950 79.4000 ;
      RECT 398.7050 78.7700 402.2950 79.4000 ;
      RECT 394.7050 78.7700 398.2950 79.4000 ;
      RECT 390.7050 78.7700 394.2950 79.4000 ;
      RECT 386.7050 78.7700 390.2950 79.4000 ;
      RECT 382.7050 78.7700 386.2950 79.4000 ;
      RECT 378.7050 78.7700 382.2950 79.4000 ;
      RECT 374.7050 78.7700 378.2950 79.4000 ;
      RECT 370.7050 78.7700 374.2950 79.4000 ;
      RECT 366.7050 78.7700 370.2950 79.4000 ;
      RECT 362.7050 78.7700 366.2950 79.4000 ;
      RECT 358.7050 78.7700 362.2950 79.4000 ;
      RECT 354.7050 78.7700 358.2950 79.4000 ;
      RECT 350.7050 78.7700 354.2950 79.4000 ;
      RECT 346.7050 78.7700 350.2950 79.4000 ;
      RECT 342.7050 78.7700 346.2950 79.4000 ;
      RECT 338.7050 78.7700 342.2950 79.4000 ;
      RECT 334.7050 78.7700 338.2950 79.4000 ;
      RECT 330.7050 78.7700 334.2950 79.4000 ;
      RECT 326.7050 78.7700 330.2950 79.4000 ;
      RECT 322.7050 78.7700 326.2950 79.4000 ;
      RECT 318.7050 78.7700 322.2950 79.4000 ;
      RECT 314.7050 78.7700 318.2950 79.4000 ;
      RECT 310.7050 78.7700 314.2950 79.4000 ;
      RECT 306.7050 78.7700 310.2950 79.4000 ;
      RECT 302.7050 78.7700 306.2950 79.4000 ;
      RECT 298.7050 78.7700 302.2950 79.4000 ;
      RECT 294.7050 78.7700 298.2950 79.4000 ;
      RECT 290.7050 78.7700 294.2950 79.4000 ;
      RECT 286.7050 78.7700 290.2950 79.4000 ;
      RECT 282.7050 78.7700 286.2950 79.4000 ;
      RECT 278.7050 78.7700 282.2950 79.4000 ;
      RECT 274.7050 78.7700 278.2950 79.4000 ;
      RECT 270.7050 78.7700 274.2950 79.4000 ;
      RECT 266.7050 78.7700 270.2950 79.4000 ;
      RECT 262.7050 78.7700 266.2950 79.4000 ;
      RECT 258.7050 78.7700 262.2950 79.4000 ;
      RECT 254.7050 78.7700 258.2950 79.4000 ;
      RECT 250.7050 78.7700 254.2950 79.4000 ;
      RECT 246.7050 78.7700 250.2950 79.4000 ;
      RECT 242.7050 78.7700 246.2950 79.4000 ;
      RECT 238.7050 78.7700 242.2950 79.4000 ;
      RECT 234.7050 78.7700 238.2950 79.4000 ;
      RECT 230.7050 78.7700 234.2950 79.4000 ;
      RECT 226.7050 78.7700 230.2950 79.4000 ;
      RECT 222.7050 78.7700 226.2950 79.4000 ;
      RECT 218.7050 78.7700 222.2950 79.4000 ;
      RECT 214.7050 78.7700 218.2950 79.4000 ;
      RECT 210.7050 78.7700 214.2950 79.4000 ;
      RECT 206.7050 78.7700 210.2950 79.4000 ;
      RECT 202.7050 78.7700 206.2950 79.4000 ;
      RECT 198.7050 78.7700 202.2950 79.4000 ;
      RECT 194.7050 78.7700 198.2950 79.4000 ;
      RECT 190.7050 78.7700 194.2950 79.4000 ;
      RECT 186.7050 78.7700 190.2950 79.4000 ;
      RECT 182.7050 78.7700 186.2950 79.4000 ;
      RECT 178.7050 78.7700 182.2950 79.4000 ;
      RECT 174.7050 78.7700 178.2950 79.4000 ;
      RECT 170.7050 78.7700 174.2950 79.4000 ;
      RECT 166.7050 78.7700 170.2950 79.4000 ;
      RECT 162.7050 78.7700 166.2950 79.4000 ;
      RECT 158.7050 78.7700 162.2950 79.4000 ;
      RECT 154.7050 78.7700 158.2950 79.4000 ;
      RECT 150.7050 78.7700 154.2950 79.4000 ;
      RECT 146.7050 78.7700 150.2950 79.4000 ;
      RECT 142.7050 78.7700 146.2950 79.4000 ;
      RECT 138.7050 78.7700 142.2950 79.4000 ;
      RECT 134.7050 78.7700 138.2950 79.4000 ;
      RECT 130.7050 78.7700 134.2950 79.4000 ;
      RECT 126.7050 78.7700 130.2950 79.4000 ;
      RECT 122.7050 78.7700 126.2950 79.4000 ;
      RECT 118.7050 78.7700 122.2950 79.4000 ;
      RECT 114.7050 78.7700 118.2950 79.4000 ;
      RECT 110.7050 78.7700 114.2950 79.4000 ;
      RECT 106.7050 78.7700 110.2950 79.4000 ;
      RECT 102.7050 78.7700 106.2950 79.4000 ;
      RECT 98.7050 78.7700 102.2950 79.4000 ;
      RECT 94.7050 78.7700 98.2950 79.4000 ;
      RECT 90.7050 78.7700 94.2950 79.4000 ;
      RECT 86.7050 78.7700 90.2950 79.4000 ;
      RECT 82.7050 78.7700 86.2950 79.4000 ;
      RECT 78.7050 78.7700 82.2950 79.4000 ;
      RECT 74.7050 78.7700 78.2950 79.4000 ;
      RECT 70.7050 78.7700 74.2950 79.4000 ;
      RECT 66.7050 78.7700 70.2950 79.4000 ;
      RECT 62.7050 78.7700 66.2950 79.4000 ;
      RECT 58.7050 78.7700 62.2950 79.4000 ;
      RECT 54.7050 78.7700 58.2950 79.4000 ;
      RECT 0.0000 78.7700 54.2950 79.4000 ;
      RECT 0.0000 51.7350 617.4000 78.7700 ;
      RECT 0.5600 51.4650 617.4000 51.7350 ;
      RECT 0.0000 47.7350 617.4000 51.4650 ;
      RECT 0.5600 47.4650 617.4000 47.7350 ;
      RECT 0.0000 43.7350 617.4000 47.4650 ;
      RECT 0.5600 43.4650 617.4000 43.7350 ;
      RECT 0.0000 39.7350 617.4000 43.4650 ;
      RECT 0.5600 39.4650 617.4000 39.7350 ;
      RECT 0.0000 35.7350 617.4000 39.4650 ;
      RECT 0.5600 35.4650 617.4000 35.7350 ;
      RECT 0.0000 31.7350 617.4000 35.4650 ;
      RECT 0.5600 31.4650 617.4000 31.7350 ;
      RECT 0.0000 27.7350 617.4000 31.4650 ;
      RECT 0.5600 27.4650 617.4000 27.7350 ;
      RECT 0.0000 0.6300 617.4000 27.4650 ;
      RECT 563.1050 0.0000 617.4000 0.6300 ;
      RECT 559.1050 0.0000 562.6950 0.6300 ;
      RECT 555.1050 0.0000 558.6950 0.6300 ;
      RECT 551.1050 0.0000 554.6950 0.6300 ;
      RECT 547.1050 0.0000 550.6950 0.6300 ;
      RECT 543.1050 0.0000 546.6950 0.6300 ;
      RECT 539.1050 0.0000 542.6950 0.6300 ;
      RECT 535.1050 0.0000 538.6950 0.6300 ;
      RECT 531.1050 0.0000 534.6950 0.6300 ;
      RECT 527.1050 0.0000 530.6950 0.6300 ;
      RECT 523.1050 0.0000 526.6950 0.6300 ;
      RECT 519.1050 0.0000 522.6950 0.6300 ;
      RECT 515.1050 0.0000 518.6950 0.6300 ;
      RECT 511.1050 0.0000 514.6950 0.6300 ;
      RECT 507.1050 0.0000 510.6950 0.6300 ;
      RECT 503.1050 0.0000 506.6950 0.6300 ;
      RECT 499.1050 0.0000 502.6950 0.6300 ;
      RECT 495.1050 0.0000 498.6950 0.6300 ;
      RECT 491.1050 0.0000 494.6950 0.6300 ;
      RECT 487.1050 0.0000 490.6950 0.6300 ;
      RECT 483.1050 0.0000 486.6950 0.6300 ;
      RECT 479.1050 0.0000 482.6950 0.6300 ;
      RECT 475.1050 0.0000 478.6950 0.6300 ;
      RECT 471.1050 0.0000 474.6950 0.6300 ;
      RECT 467.1050 0.0000 470.6950 0.6300 ;
      RECT 463.1050 0.0000 466.6950 0.6300 ;
      RECT 459.1050 0.0000 462.6950 0.6300 ;
      RECT 455.1050 0.0000 458.6950 0.6300 ;
      RECT 451.1050 0.0000 454.6950 0.6300 ;
      RECT 447.1050 0.0000 450.6950 0.6300 ;
      RECT 443.1050 0.0000 446.6950 0.6300 ;
      RECT 439.1050 0.0000 442.6950 0.6300 ;
      RECT 435.1050 0.0000 438.6950 0.6300 ;
      RECT 431.1050 0.0000 434.6950 0.6300 ;
      RECT 427.1050 0.0000 430.6950 0.6300 ;
      RECT 423.1050 0.0000 426.6950 0.6300 ;
      RECT 419.1050 0.0000 422.6950 0.6300 ;
      RECT 415.1050 0.0000 418.6950 0.6300 ;
      RECT 411.1050 0.0000 414.6950 0.6300 ;
      RECT 407.1050 0.0000 410.6950 0.6300 ;
      RECT 403.1050 0.0000 406.6950 0.6300 ;
      RECT 399.1050 0.0000 402.6950 0.6300 ;
      RECT 395.1050 0.0000 398.6950 0.6300 ;
      RECT 391.1050 0.0000 394.6950 0.6300 ;
      RECT 387.1050 0.0000 390.6950 0.6300 ;
      RECT 383.1050 0.0000 386.6950 0.6300 ;
      RECT 379.1050 0.0000 382.6950 0.6300 ;
      RECT 375.1050 0.0000 378.6950 0.6300 ;
      RECT 371.1050 0.0000 374.6950 0.6300 ;
      RECT 367.1050 0.0000 370.6950 0.6300 ;
      RECT 363.1050 0.0000 366.6950 0.6300 ;
      RECT 359.1050 0.0000 362.6950 0.6300 ;
      RECT 355.1050 0.0000 358.6950 0.6300 ;
      RECT 351.1050 0.0000 354.6950 0.6300 ;
      RECT 347.1050 0.0000 350.6950 0.6300 ;
      RECT 343.1050 0.0000 346.6950 0.6300 ;
      RECT 339.1050 0.0000 342.6950 0.6300 ;
      RECT 335.1050 0.0000 338.6950 0.6300 ;
      RECT 331.1050 0.0000 334.6950 0.6300 ;
      RECT 327.1050 0.0000 330.6950 0.6300 ;
      RECT 323.1050 0.0000 326.6950 0.6300 ;
      RECT 319.1050 0.0000 322.6950 0.6300 ;
      RECT 315.1050 0.0000 318.6950 0.6300 ;
      RECT 311.1050 0.0000 314.6950 0.6300 ;
      RECT 307.1050 0.0000 310.6950 0.6300 ;
      RECT 303.1050 0.0000 306.6950 0.6300 ;
      RECT 299.1050 0.0000 302.6950 0.6300 ;
      RECT 295.1050 0.0000 298.6950 0.6300 ;
      RECT 291.1050 0.0000 294.6950 0.6300 ;
      RECT 287.1050 0.0000 290.6950 0.6300 ;
      RECT 283.1050 0.0000 286.6950 0.6300 ;
      RECT 279.1050 0.0000 282.6950 0.6300 ;
      RECT 275.1050 0.0000 278.6950 0.6300 ;
      RECT 271.1050 0.0000 274.6950 0.6300 ;
      RECT 267.1050 0.0000 270.6950 0.6300 ;
      RECT 263.1050 0.0000 266.6950 0.6300 ;
      RECT 259.1050 0.0000 262.6950 0.6300 ;
      RECT 255.1050 0.0000 258.6950 0.6300 ;
      RECT 251.1050 0.0000 254.6950 0.6300 ;
      RECT 247.1050 0.0000 250.6950 0.6300 ;
      RECT 243.1050 0.0000 246.6950 0.6300 ;
      RECT 239.1050 0.0000 242.6950 0.6300 ;
      RECT 235.1050 0.0000 238.6950 0.6300 ;
      RECT 231.1050 0.0000 234.6950 0.6300 ;
      RECT 227.1050 0.0000 230.6950 0.6300 ;
      RECT 223.1050 0.0000 226.6950 0.6300 ;
      RECT 219.1050 0.0000 222.6950 0.6300 ;
      RECT 215.1050 0.0000 218.6950 0.6300 ;
      RECT 211.1050 0.0000 214.6950 0.6300 ;
      RECT 207.1050 0.0000 210.6950 0.6300 ;
      RECT 203.1050 0.0000 206.6950 0.6300 ;
      RECT 199.1050 0.0000 202.6950 0.6300 ;
      RECT 195.1050 0.0000 198.6950 0.6300 ;
      RECT 191.1050 0.0000 194.6950 0.6300 ;
      RECT 187.1050 0.0000 190.6950 0.6300 ;
      RECT 183.1050 0.0000 186.6950 0.6300 ;
      RECT 179.1050 0.0000 182.6950 0.6300 ;
      RECT 175.1050 0.0000 178.6950 0.6300 ;
      RECT 171.1050 0.0000 174.6950 0.6300 ;
      RECT 167.1050 0.0000 170.6950 0.6300 ;
      RECT 163.1050 0.0000 166.6950 0.6300 ;
      RECT 159.1050 0.0000 162.6950 0.6300 ;
      RECT 155.1050 0.0000 158.6950 0.6300 ;
      RECT 151.1050 0.0000 154.6950 0.6300 ;
      RECT 147.1050 0.0000 150.6950 0.6300 ;
      RECT 143.1050 0.0000 146.6950 0.6300 ;
      RECT 139.1050 0.0000 142.6950 0.6300 ;
      RECT 135.1050 0.0000 138.6950 0.6300 ;
      RECT 131.1050 0.0000 134.6950 0.6300 ;
      RECT 127.1050 0.0000 130.6950 0.6300 ;
      RECT 123.1050 0.0000 126.6950 0.6300 ;
      RECT 119.1050 0.0000 122.6950 0.6300 ;
      RECT 115.1050 0.0000 118.6950 0.6300 ;
      RECT 111.1050 0.0000 114.6950 0.6300 ;
      RECT 107.1050 0.0000 110.6950 0.6300 ;
      RECT 103.1050 0.0000 106.6950 0.6300 ;
      RECT 99.1050 0.0000 102.6950 0.6300 ;
      RECT 95.1050 0.0000 98.6950 0.6300 ;
      RECT 91.1050 0.0000 94.6950 0.6300 ;
      RECT 87.1050 0.0000 90.6950 0.6300 ;
      RECT 83.1050 0.0000 86.6950 0.6300 ;
      RECT 79.1050 0.0000 82.6950 0.6300 ;
      RECT 75.1050 0.0000 78.6950 0.6300 ;
      RECT 71.1050 0.0000 74.6950 0.6300 ;
      RECT 67.1050 0.0000 70.6950 0.6300 ;
      RECT 63.1050 0.0000 66.6950 0.6300 ;
      RECT 59.1050 0.0000 62.6950 0.6300 ;
      RECT 55.1050 0.0000 58.6950 0.6300 ;
      RECT 0.0000 0.0000 54.6950 0.6300 ;
    LAYER M2 ;
      RECT 0.0000 0.0000 617.4000 79.4000 ;
    LAYER M3 ;
      RECT 0.0000 0.0000 617.4000 79.4000 ;
    LAYER M4 ;
      RECT 0.0000 0.0000 617.4000 79.4000 ;
  END
END sram_128b_w16

END LIBRARY
